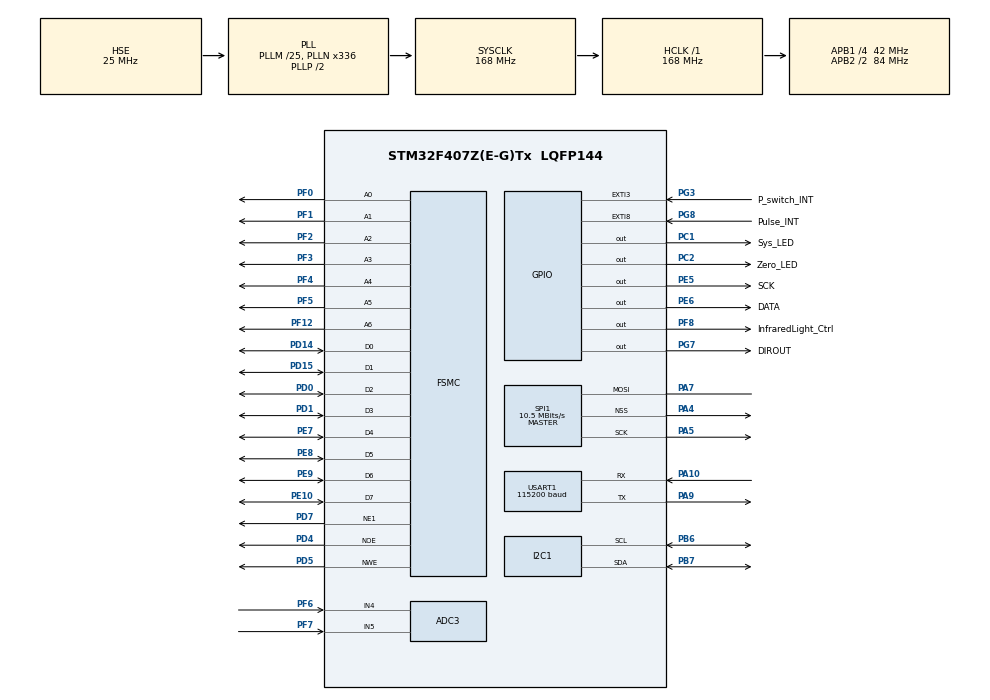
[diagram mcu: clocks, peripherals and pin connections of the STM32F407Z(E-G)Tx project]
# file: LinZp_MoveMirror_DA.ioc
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ADC3.Channel-0\#ChannelRegularConversion=ADC_CHANNEL_4
ADC3.NbrOfConversionFlag=1
ADC3.Rank-0\#ChannelRegularConversion=1
ADC3.SamplingTime-0\#ChannelRegularConversion=ADC_SAMPLETIME_3CYCLES
ADC3.ScanConvMode=ENABLE
Dma.I2C1_RX.0.Direction=DMA_PERIPH_TO_MEMORY
Dma.I2C1_RX.0.FIFOMode=DMA_FIFOMODE_DISABLE
Dma.I2C1_RX.0.Instance=DMA1_Stream0
Dma.I2C1_RX.0.MemDataAlignment=DMA_MDATAALIGN_BYTE
Dma.I2C1_RX.0.MemInc=DMA_MINC_ENABLE
Dma.I2C1_RX.0.Mode=DMA_NORMAL
Dma.I2C1_RX.0.PeriphDataAlignment=DMA_PDATAALIGN_BYTE
Dma.I2C1_RX.0.PeriphInc=DMA_PINC_DISABLE
Dma.I2C1_RX.0.Priority=DMA_PRIORITY_LOW
Dma.I2C1_TX.1.Direction=DMA_MEMORY_TO_PERIPH
Dma.I2C1_TX.1.FIFOMode=DMA_FIFOMODE_DISABLE
Dma.I2C1_TX.1.Instance=DMA1_Stream6
Dma.I2C1_TX.1.MemDataAlignment=DMA_MDATAALIGN_BYTE
Dma.I2C1_TX.1.MemInc=DMA_MINC_ENABLE
Dma.I2C1_TX.1.Mode=DMA_NORMAL
Dma.I2C1_TX.1.PeriphDataAlignment=DMA_PDATAALIGN_BYTE
Dma.I2C1_TX.1.PeriphInc=DMA_PINC_DISABLE
Dma.I2C1_TX.1.Priority=DMA_PRIORITY_LOW
Dma.Request0=I2C1_RX
Dma.Request1=I2C1_TX
Mcu.Family=STM32F4
Mcu.Name=STM32F407Z(E-G)Tx
Mcu.Package=LQFP144
NVIC.DMA1_Stream0_IRQn=true\:0\:0\:false\:false\:true\:false
NVIC.DMA1_Stream6_IRQn=true\:0\:0\:false\:false\:true\:false
NVIC.EXTI3_IRQn=true\:2\:0\:true\:false\:true\:true
NVIC.EXTI9_5_IRQn=true\:1\:0\:true\:false\:true\:true
NVIC.PriorityGroup=NVIC_PRIORITYGROUP_3
NVIC.TIM3_IRQn=true\:3\:0\:true\:false\:true\:true
NVIC.TIM4_IRQn=true\:4\:0\:true\:false\:true\:true
NVIC.USART1_IRQn=true\:0\:0\:true\:false\:true\:true
PA10.Mode=Asynchronous
PA10.Signal=USART1_RX
PA4.Mode=NSS_Signal_Hard_Output
PA4.Signal=SPI1_NSS
PA5.Mode=Simplex_Bidirectional_Master
PA5.Signal=SPI1_SCK
PA7.Mode=Simplex_Bidirectional_Master
PA7.Signal=SPI1_MOSI
PA9.Mode=Asynchronous
PA9.Signal=USART1_TX
PB6.Mode=I2C
PB6.Signal=I2C1_SCL
PB7.Mode=I2C
PB7.Signal=I2C1_SDA
PC1.GPIO_Label=Sys_LED
PC1.GPIO_PuPd=GPIO_PULLUP
PC1.GPIO_Speed=GPIO_SPEED_FREQ_HIGH
PC1.PinState=GPIO_PIN_SET
PC1.Signal=GPIO_Output
PC2.GPIO_Label=Zero_LED
PC2.GPIO_PuPd=GPIO_PULLUP
PC2.GPIO_Speed=GPIO_SPEED_FREQ_HIGH
PC2.PinState=GPIO_PIN_SET
PC2.Signal=GPIO_Output
PD0.Signal=FSMC_D2_DA2
PD1.Signal=FSMC_D3_DA3
PD14.Signal=FSMC_D0_DA0
PD15.Signal=FSMC_D1_DA1
PD4.Signal=FSMC_NOE
PD5.Signal=FSMC_NWE
PD7.Mode=NorPsramChipSelect1_1
PD7.Signal=FSMC_NE1
PE10.Signal=FSMC_D7_DA7
PE5.GPIO_Label=SCK
PE5.Signal=GPIO_Output
PE6.GPIO_Label=DATA
PE6.Signal=GPIO_Output
PE7.Signal=FSMC_D4_DA4
PE8.Signal=FSMC_D5_DA5
PE9.Signal=FSMC_D6_DA6
PF0.Signal=FSMC_A0
PF1.Signal=FSMC_A1
PF12.Signal=FSMC_A6
PF2.Signal=FSMC_A2
PF3.Signal=FSMC_A3
PF4.Signal=FSMC_A4
PF5.Signal=FSMC_A5
PF6.Mode=IN4
PF6.Signal=ADC3_IN4
PF7.Mode=IN5
PF7.Signal=ADC3_IN5
PF8.GPIO_Label=InfraredLight_Ctrl
PF8.GPIO_PuPd=GPIO_PULLDOWN
PF8.Signal=GPIO_Output
PG3.GPIO_Label=P_switch_INT
PG3.Signal=GPXTI3
PG7.GPIO_Label=DIROUT
PG7.GPIO_PuPd=GPIO_NOPULL
PG7.Signal=GPIO_Output
PG8.GPIO_Label=Pulse_INT
PG8.Signal=GPXTI8
PH0-OSC_IN.Mode=HSE-External-Oscillator
PH0-OSC_IN.Signal=RCC_OSC_IN
PH1-OSC_OUT.Mode=HSE-External-Oscillator
PH1-OSC_OUT.Signal=RCC_OSC_OUT
ProjectManager.HeapSize=0x200
ProjectManager.StackSize=0x400
ProjectManager.TargetToolchain=MDK-ARM V5
RCC.48MHZClocksFreq_Value=84000000
RCC.AHBFreq_Value=168000000
RCC.APB1CLKDivider=RCC_HCLK_DIV4
RCC.APB1Freq_Value=42000000
RCC.APB1TimFreq_Value=84000000
RCC.APB2CLKDivider=RCC_HCLK_DIV2
RCC.APB2Freq_Value=84000000
RCC.APB2TimFreq_Value=168000000
RCC.CortexFreq_Value=168000000
RCC.HCLKFreq_Value=168000000
RCC.HSE_VALUE=25000000
RCC.HSI_VALUE=16000000
RCC.LSE_VALUE=32768
RCC.PLLM=25
RCC.PLLN=336
RCC.PLLSourceVirtual=RCC_PLLSOURCE_HSE
RCC.SYSCLKFreq_VALUE=168000000
RCC.SYSCLKSource=RCC_SYSCLKSOURCE_PLLCLK
RCC.VCOOutputFreq_Value=336000000
SH.FSMC_A0.0=FSMC_A0,7b-a1
SH.FSMC_A1.0=FSMC_A1,7b-a1
SH.FSMC_A2.0=FSMC_A2,7b-a1
SH.FSMC_A3.0=FSMC_A3,7b-a1
SH.FSMC_A4.0=FSMC_A4,7b-a1
SH.FSMC_A5.0=FSMC_A5,7b-a1
SH.FSMC_A6.0=FSMC_A6,7b-a1
SH.FSMC_D0_DA0.0=FSMC_D0,8b-d1
SH.FSMC_D1_DA1.0=FSMC_D1,8b-d1
SH.FSMC_D2_DA2.0=FSMC_D2,8b-d1
SH.FSMC_D3_DA3.0=FSMC_D3,8b-d1
SH.FSMC_D4_DA4.0=FSMC_D4,8b-d1
SH.FSMC_D5_DA5.0=FSMC_D5,8b-d1
SH.FSMC_D6_DA6.0=FSMC_D6,8b-d1
SH.FSMC_D7_DA7.0=FSMC_D7,8b-d1
SH.FSMC_NOE.0=FSMC_NOE,Sram1
SH.FSMC_NWE.0=FSMC_NWE,Sram1
SPI1.BaudRatePrescaler=SPI_BAUDRATEPRESCALER_8
SPI1.CLKPhase=SPI_PHASE_2EDGE
SPI1.CalculateBaudRate=10.5 MBits/s
SPI1.Direction=SPI_DIRECTION_1LINE
SPI1.Mode=SPI_MODE_MASTER
SPI1.VirtualNSS=VM_NSSHARD
SPI1.VirtualType=VM_MASTER
TIM3.Period=1
TIM3.Prescaler=84
TIM4.Period=100
TIM4.Prescaler=84
USART1.BaudRate=115200
USART1.OverSampling=UART_OVERSAMPLING_8
USART1.VirtualMode=VM_ASYNC
VP_TIM3_VS_ClockSourceINT.Mode=Internal
VP_TIM4_VS_ClockSourceINT.Mode=Internal
board=MoveMirrorFinal_pwm

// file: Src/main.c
/**
  ******************************************************************************
  * @file           : main.c
  * @brief          : Main program body
  ******************************************************************************
  ** This notice applies to any and all portions of this file
  * that are not between comment pairs USER CODE BEGIN and
  * USER CODE END. Other portions of this file, whether
  * inserted by the user or by software development tools
  * are owned by their respective copyright owners.
  *
  * COPYRIGHT(c) 2018 STMicroelectronics
  *
  * Redistribution and use in source and binary forms, with or without modification,
  * are permitted provided that the following conditions are met:
  *   1. Redistributions of source code must retain the above copyright notice,
  *      this list of conditions and the following disclaimer.
  *   2. Redistributions in binary form must reproduce the above copyright notice,
  *      this list of conditions and the following disclaimer in the documentation
  *      and/or other materials provided with the distribution.
  *   3. Neither the name of STMicroelectronics nor the names of its contributors
  *      may be used to endorse or promote products derived from this software
  *      without specific prior written permission.
  *
  * THIS SOFTWARE IS PROVIDED BY THE COPYRIGHT HOLDERS AND CONTRIBUTORS "AS IS"
  * AND ANY EXPRESS OR IMPLIED WARRANTIES, INCLUDING, BUT NOT LIMITED TO, THE
  * IMPLIED WARRANTIES OF MERCHANTABILITY AND FITNESS FOR A PARTICULAR PURPOSE ARE
  * DISCLAIMED. IN NO EVENT SHALL THE COPYRIGHT HOLDER OR CONTRIBUTORS BE LIABLE
  * FOR ANY DIRECT, INDIRECT, INCIDENTAL, SPECIAL, EXEMPLARY, OR CONSEQUENTIAL
  * DAMAGES (INCLUDING, BUT NOT LIMITED TO, PROCUREMENT OF SUBSTITUTE GOODS OR
  * SERVICES; LOSS OF USE, DATA, OR PROFITS; OR BUSINESS INTERRUPTION) HOWEVER
  * CAUSED AND ON ANY THEORY OF LIABILITY, WHETHER IN CONTRACT, STRICT LIABILITY,
  * OR TORT (INCLUDING NEGLIGENCE OR OTHERWISE) ARISING IN ANY WAY OUT OF THE USE
  * OF THIS SOFTWARE, EVEN IF ADVISED OF THE POSSIBILITY OF SUCH DAMAGE.
  *
  ******************************************************************************
  */
#include "main.h"
#include "stm32f4xx_hal.h"

/* USER CODE BEGIN Includes */
#include "sys.h"
/* USER CODE END Includes */

ADC_HandleTypeDef hadc3;

I2C_HandleTypeDef hi2c1;
DMA_HandleTypeDef hdma_i2c1_rx;
DMA_HandleTypeDef hdma_i2c1_tx;

SPI_HandleTypeDef hspi1;

TIM_HandleTypeDef htim3;
TIM_HandleTypeDef htim4;

UART_HandleTypeDef huart1;

SRAM_HandleTypeDef hsram1;

/* USER CODE BEGIN PV */
/* Private variables ---------------------------------------------------------*/

/* USER CODE END PV */

void SystemClock_Config(void);
static void MX_GPIO_Init(void);
static void MX_DMA_Init(void);
static void MX_FSMC_Init(void);
static void MX_USART1_UART_Init(void);
static void MX_TIM3_Init(void);
static void MX_TIM4_Init(void);
static void MX_SPI1_Init(void);
static void MX_I2C1_Init(void);
static void MX_ADC3_Init(void);

/* USER CODE BEGIN PFP */
/* Private function prototypes -----------------------------------------------*/

/* USER CODE END PFP */

int main(void)
{

  /* MCU Configuration----------------------------------------------------------*/

  /* Reset of all peripherals, Initializes the Flash interface and the Systick. */
  HAL_Init();

  /* Configure the system clock */
  SystemClock_Config();

  /* Initialize all configured peripherals */
  MX_GPIO_Init();
  MX_DMA_Init();
  MX_FSMC_Init();
  MX_USART1_UART_Init();
  MX_TIM3_Init();
  MX_TIM4_Init();
  MX_SPI1_Init();
  MX_I2C1_Init();
  MX_ADC3_Init();
  /* USER CODE BEGIN 2 */
	DAC_init();
	HAL_UART_Receive_IT(&huart1,&Uart1_Data,1);//给接收到的数据定向，存在Uart1_Data_buffer[10]//__HAL_UART_ENABLE_IT(&huart1,UART_IT_RXNE); //开启接收完成中断
	//HAL_UART_Receive_IT(&huart3,&Uart3_Data,1);//给接收到的数据定向，存在Uart1_Data_buffer[10]//__HAL_UART_ENABLE_IT(&huart1,UART_IT_RXNE); //开启接收完成中断

	//HAL_Delay_ms(15000);
	////////////////////////////////////////////////////////////////////////////
	AD5245_Write(LightIntensity);//给AD5245写入初始值0x35=53，6.4v//8是10.6V

	//HAL_TIM_PWM_Start(&htim8,TIM_CHANNEL_1);//tim8开启 PWM 通道 1
	ResetCount = 0;       //复位计数
	ProcessFlag=ResetFlag;//开机复位
	//ProcessFlag=DebugFlag;//开机复位
	SystemReset();
	HAL_TIM_Base_Start_IT(&htim3);   //tim3中断开启,用于动镜的加速和减速
	HAL_TIM_Base_Start_IT(&htim4);   //tim4中断开启，用于调试信息输出，以及运动失调的复位
  /* USER CODE END 2 */

  /* Infinite loop */
  while (1)
  {

  /* USER CODE BEGIN 3 */
	//	SetOutput(-584287);

	//uint8_t ADDR_AD5245_Write = 0x58;//01011000
	//uint8_t data = 0x35;//53
	//HAL_I2C_Mem_Write(&hi2c1, ADDR_AD5245_Write, 0, I2C_MEMADD_SIZE_8BIT,&data,1,0xff);
//	HAL_I2C_Master_Transmit_DMA(&hi2c1,ADDR_AD5245_Write,&data,1);

//	ADC_Value4 = Get_Adc(4);
//	ADC_Value5 = Get_Adc(5);

//	HAL_Delay(5);
//	HAL_I2C_Mem_Write(&hi2c1, ADDR_24LCxx_Read, 0, I2C_MEMADD_SIZE_8BIT,&val,1,0xff);

		//SetOutput(300000);
	//	Write_AD_5791(320000);
//		HAL_Delay_ms(1000);
//		HAL_GPIO_WritePin(GPIOC, GPIO_PIN_1, GPIO_PIN_RESET);
//		HAL_Delay_ms(1000);
//		HAL_GPIO_WritePin(GPIOC, GPIO_PIN_1, GPIO_PIN_SET);
  }
  /* USER CODE END 3 */

}

void SystemClock_Config(void)
{

  RCC_OscInitTypeDef RCC_OscInitStruct;
  RCC_ClkInitTypeDef RCC_ClkInitStruct;

    /**Configure the main internal regulator output voltage
    */
  __HAL_RCC_PWR_CLK_ENABLE();

  __HAL_PWR_VOLTAGESCALING_CONFIG(PWR_REGULATOR_VOLTAGE_SCALE1);

    /**Initializes the CPU, AHB and APB busses clocks
    */
  RCC_OscInitStruct.OscillatorType = RCC_OSCILLATORTYPE_HSE;
  RCC_OscInitStruct.HSEState = RCC_HSE_ON;
  RCC_OscInitStruct.PLL.PLLState = RCC_PLL_ON;
  RCC_OscInitStruct.PLL.PLLSource = RCC_PLLSOURCE_HSE;
  RCC_OscInitStruct.PLL.PLLM = 25;
  RCC_OscInitStruct.PLL.PLLN = 336;
  RCC_OscInitStruct.PLL.PLLP = RCC_PLLP_DIV2;
  RCC_OscInitStruct.PLL.PLLQ = 4;
  if (HAL_RCC_OscConfig(&RCC_OscInitStruct) != HAL_OK)
  {
    _Error_Handler(__FILE__, __LINE__);
  }

    /**Initializes the CPU, AHB and APB busses clocks
    */
  RCC_ClkInitStruct.ClockType = RCC_CLOCKTYPE_HCLK|RCC_CLOCKTYPE_SYSCLK
                              |RCC_CLOCKTYPE_PCLK1|RCC_CLOCKTYPE_PCLK2;
  RCC_ClkInitStruct.SYSCLKSource = RCC_SYSCLKSOURCE_PLLCLK;
  RCC_ClkInitStruct.AHBCLKDivider = RCC_SYSCLK_DIV1;
  RCC_ClkInitStruct.APB1CLKDivider = RCC_HCLK_DIV4;
  RCC_ClkInitStruct.APB2CLKDivider = RCC_HCLK_DIV2;

  if (HAL_RCC_ClockConfig(&RCC_ClkInitStruct, FLASH_LATENCY_5) != HAL_OK)
  {
    _Error_Handler(__FILE__, __LINE__);
  }

    /**Configure the Systick interrupt time
    */
  HAL_SYSTICK_Config(HAL_RCC_GetHCLKFreq()/1000);

    /**Configure the Systick
    */
  HAL_SYSTICK_CLKSourceConfig(SYSTICK_CLKSOURCE_HCLK);

  /* SysTick_IRQn interrupt configuration */
  HAL_NVIC_SetPriority(SysTick_IRQn, 0, 0);
}

/* ADC3 init function */
static void MX_ADC3_Init(void)
{

  ADC_ChannelConfTypeDef sConfig;

    /**Configure the global features of the ADC (Clock, Resolution, Data Alignment and number of conversion)
    */
  hadc3.Instance = ADC3;
  hadc3.Init.ClockPrescaler = ADC_CLOCK_SYNC_PCLK_DIV4;
  hadc3.Init.Resolution = ADC_RESOLUTION_12B;
  hadc3.Init.ScanConvMode = ENABLE;
  hadc3.Init.ContinuousConvMode = DISABLE;
  hadc3.Init.DiscontinuousConvMode = DISABLE;
  hadc3.Init.ExternalTrigConvEdge = ADC_EXTERNALTRIGCONVEDGE_NONE;
  hadc3.Init.ExternalTrigConv = ADC_SOFTWARE_START;
  hadc3.Init.DataAlign = ADC_DATAALIGN_RIGHT;
  hadc3.Init.NbrOfConversion = 1;
  hadc3.Init.DMAContinuousRequests = DISABLE;
  hadc3.Init.EOCSelection = ADC_EOC_SINGLE_CONV;
  if (HAL_ADC_Init(&hadc3) != HAL_OK)
  {
    _Error_Handler(__FILE__, __LINE__);
  }

    /**Configure for the selected ADC regular channel its corresponding rank in the sequencer and its sample time.
    */
  sConfig.Channel = ADC_CHANNEL_4;
  sConfig.Rank = 1;
  sConfig.SamplingTime = ADC_SAMPLETIME_3CYCLES;
  if (HAL_ADC_ConfigChannel(&hadc3, &sConfig) != HAL_OK)
  {
    _Error_Handler(__FILE__, __LINE__);
  }

}

/* I2C1 init function */
static void MX_I2C1_Init(void)
{

  hi2c1.Instance = I2C1;
  hi2c1.Init.ClockSpeed = 100000;
  hi2c1.Init.DutyCycle = I2C_DUTYCYCLE_2;
  hi2c1.Init.OwnAddress1 = 0;
  hi2c1.Init.AddressingMode = I2C_ADDRESSINGMODE_7BIT;
  hi2c1.Init.DualAddressMode = I2C_DUALADDRESS_DISABLE;
  hi2c1.Init.OwnAddress2 = 0;
  hi2c1.Init.GeneralCallMode = I2C_GENERALCALL_DISABLE;
  hi2c1.Init.NoStretchMode = I2C_NOSTRETCH_DISABLE;
  if (HAL_I2C_Init(&hi2c1) != HAL_OK)
  {
    _Error_Handler(__FILE__, __LINE__);
  }

}

/* SPI1 init function */
static void MX_SPI1_Init(void)
{

  /* SPI1 parameter configuration*/
  hspi1.Instance = SPI1;
  hspi1.Init.Mode = SPI_MODE_MASTER;
  hspi1.Init.Direction = SPI_DIRECTION_1LINE;
  hspi1.Init.DataSize = SPI_DATASIZE_8BIT;
  hspi1.Init.CLKPolarity = SPI_POLARITY_LOW;
  hspi1.Init.CLKPhase = SPI_PHASE_2EDGE;
  hspi1.Init.NSS = SPI_NSS_HARD_OUTPUT;
  hspi1.Init.BaudRatePrescaler = SPI_BAUDRATEPRESCALER_8;
  hspi1.Init.FirstBit = SPI_FIRSTBIT_MSB;
  hspi1.Init.TIMode = SPI_TIMODE_DISABLE;
  hspi1.Init.CRCCalculation = SPI_CRCCALCULATION_DISABLE;
  hspi1.Init.CRCPolynomial = 10;
  if (HAL_SPI_Init(&hspi1) != HAL_OK)
  {
    _Error_Handler(__FILE__, __LINE__);
  }

}

/* TIM3 init function */
static void MX_TIM3_Init(void)
{

  TIM_ClockConfigTypeDef sClockSourceConfig;
  TIM_MasterConfigTypeDef sMasterConfig;

  htim3.Instance = TIM3;
  htim3.Init.Prescaler = 84;
  htim3.Init.CounterMode = TIM_COUNTERMODE_UP;
  htim3.Init.Period = 1;
  htim3.Init.ClockDivision = TIM_CLOCKDIVISION_DIV1;
  if (HAL_TIM_Base_Init(&htim3) != HAL_OK)
  {
    _Error_Handler(__FILE__, __LINE__);
  }

  sClockSourceConfig.ClockSource = TIM_CLOCKSOURCE_INTERNAL;
  if (HAL_TIM_ConfigClockSource(&htim3, &sClockSourceConfig) != HAL_OK)
  {
    _Error_Handler(__FILE__, __LINE__);
  }

  sMasterConfig.MasterOutputTrigger = TIM_TRGO_RESET;
  sMasterConfig.MasterSlaveMode = TIM_MASTERSLAVEMODE_DISABLE;
  if (HAL_TIMEx_MasterConfigSynchronization(&htim3, &sMasterConfig) != HAL_OK)
  {
    _Error_Handler(__FILE__, __LINE__);
  }

}

/* TIM4 init function */
static void MX_TIM4_Init(void)
{

  TIM_ClockConfigTypeDef sClockSourceConfig;
  TIM_MasterConfigTypeDef sMasterConfig;

  htim4.Instance = TIM4;
  htim4.Init.Prescaler = 84;
  htim4.Init.CounterMode = TIM_COUNTERMODE_UP;
  htim4.Init.Period = 100;
  htim4.Init.ClockDivision = TIM_CLOCKDIVISION_DIV1;
  if (HAL_TIM_Base_Init(&htim4) != HAL_OK)
  {
    _Error_Handler(__FILE__, __LINE__);
  }

  sClockSourceConfig.ClockSource = TIM_CLOCKSOURCE_INTERNAL;
  if (HAL_TIM_ConfigClockSource(&htim4, &sClockSourceConfig) != HAL_OK)
  {
    _Error_Handler(__FILE__, __LINE__);
  }

  sMasterConfig.MasterOutputTrigger = TIM_TRGO_RESET;
  sMasterConfig.MasterSlaveMode = TIM_MASTERSLAVEMODE_DISABLE;
  if (HAL_TIMEx_MasterConfigSynchronization(&htim4, &sMasterConfig) != HAL_OK)
  {
    _Error_Handler(__FILE__, __LINE__);
  }

}

/* USART1 init function */
static void MX_USART1_UART_Init(void)
{

  huart1.Instance = USART1;
  huart1.Init.BaudRate = 115200;
  huart1.Init.WordLength = UART_WORDLENGTH_8B;
  huart1.Init.StopBits = UART_STOPBITS_1;
  huart1.Init.Parity = UART_PARITY_NONE;
  huart1.Init.Mode = UART_MODE_TX_RX;
  huart1.Init.HwFlowCtl = UART_HWCONTROL_NONE;
  huart1.Init.OverSampling = UART_OVERSAMPLING_8;
  if (HAL_UART_Init(&huart1) != HAL_OK)
  {
    _Error_Handler(__FILE__, __LINE__);
  }

}

static void MX_DMA_Init(void)
{
  /* DMA controller clock enable */
  __HAL_RCC_DMA1_CLK_ENABLE();

  /* DMA interrupt init */
  /* DMA1_Stream0_IRQn interrupt configuration */
  HAL_NVIC_SetPriority(DMA1_Stream0_IRQn, 0, 0);
  HAL_NVIC_EnableIRQ(DMA1_Stream0_IRQn);
  /* DMA1_Stream6_IRQn interrupt configuration */
  HAL_NVIC_SetPriority(DMA1_Stream6_IRQn, 0, 0);
  HAL_NVIC_EnableIRQ(DMA1_Stream6_IRQn);

}

/** Configure pins as
        * Analog
        * Input
        * Output
        * EVENT_OUT
        * EXTI
*/
static void MX_GPIO_Init(void)
{

  GPIO_InitTypeDef GPIO_InitStruct;

  /* GPIO Ports Clock Enable */
  __HAL_RCC_GPIOE_CLK_ENABLE();
  __HAL_RCC_GPIOF_CLK_ENABLE();
  __HAL_RCC_GPIOH_CLK_ENABLE();
  __HAL_RCC_GPIOC_CLK_ENABLE();
  __HAL_RCC_GPIOA_CLK_ENABLE();
  __HAL_RCC_GPIOD_CLK_ENABLE();
  __HAL_RCC_GPIOG_CLK_ENABLE();
  __HAL_RCC_GPIOB_CLK_ENABLE();

  /*Configure GPIO pin Output Level */
  HAL_GPIO_WritePin(GPIOE, SCK_Pin|DATA_Pin, GPIO_PIN_RESET);

  /*Configure GPIO pin Output Level */
  HAL_GPIO_WritePin(InfraredLight_Ctrl_GPIO_Port, InfraredLight_Ctrl_Pin, GPIO_PIN_RESET);

  /*Configure GPIO pin Output Level */
  HAL_GPIO_WritePin(GPIOC, GPIO_PIN_1|GPIO_PIN_2, GPIO_PIN_SET);

  /*Configure GPIO pin Output Level */
  HAL_GPIO_WritePin(GPIOG, GPIO_PIN_2|GPIO_PIN_7, GPIO_PIN_RESET);

  /*Configure GPIO pin Output Level */
  HAL_GPIO_WritePin(GPIOC, GPIO_PIN_7|GPIO_PIN_8|GPIO_PIN_9, GPIO_PIN_RESET);

  /*Configure GPIO pins : SCK_Pin DATA_Pin */
  GPIO_InitStruct.Pin = SCK_Pin|DATA_Pin;
  GPIO_InitStruct.Mode = GPIO_MODE_OUTPUT_PP;
  GPIO_InitStruct.Pull = GPIO_NOPULL;
  GPIO_InitStruct.Speed = GPIO_SPEED_FREQ_LOW;
  HAL_GPIO_Init(GPIOE, &GPIO_InitStruct);

  /*Configure GPIO pin : InfraredLight_Ctrl_Pin */
  GPIO_InitStruct.Pin = InfraredLight_Ctrl_Pin;
  GPIO_InitStruct.Mode = GPIO_MODE_OUTPUT_PP;
  GPIO_InitStruct.Pull = GPIO_PULLDOWN;
  GPIO_InitStruct.Speed = GPIO_SPEED_FREQ_LOW;
  HAL_GPIO_Init(InfraredLight_Ctrl_GPIO_Port, &GPIO_InitStruct);

  /*Configure GPIO pins : PC1 PC2 */
  GPIO_InitStruct.Pin = GPIO_PIN_1|GPIO_PIN_2;
  GPIO_InitStruct.Mode = GPIO_MODE_OUTPUT_PP;
  GPIO_InitStruct.Pull = GPIO_PULLUP;
  GPIO_InitStruct.Speed = GPIO_SPEED_FREQ_HIGH;
  HAL_GPIO_Init(GPIOC, &GPIO_InitStruct);

  /*Configure GPIO pins : PG2 PG7 */
  GPIO_InitStruct.Pin = GPIO_PIN_2|GPIO_PIN_7;
  GPIO_InitStruct.Mode = GPIO_MODE_OUTPUT_PP;
  GPIO_InitStruct.Pull = GPIO_NOPULL;
  GPIO_InitStruct.Speed = GPIO_SPEED_FREQ_LOW;
  HAL_GPIO_Init(GPIOG, &GPIO_InitStruct);

  /*Configure GPIO pins : PG3 PG8 */
  GPIO_InitStruct.Pin = GPIO_PIN_3|GPIO_PIN_8;
  GPIO_InitStruct.Mode = GPIO_MODE_IT_RISING;
  GPIO_InitStruct.Pull = GPIO_NOPULL;
  HAL_GPIO_Init(GPIOG, &GPIO_InitStruct);

  /*Configure GPIO pins : PC7 PC8 PC9 */
  GPIO_InitStruct.Pin = GPIO_PIN_7|GPIO_PIN_8|GPIO_PIN_9;
  GPIO_InitStruct.Mode = GPIO_MODE_OUTPUT_PP;
  GPIO_InitStruct.Pull = GPIO_NOPULL;
  GPIO_InitStruct.Speed = GPIO_SPEED_FREQ_LOW;
  HAL_GPIO_Init(GPIOC, &GPIO_InitStruct);

  /* EXTI interrupt init*/
  HAL_NVIC_SetPriority(EXTI3_IRQn, 2, 0);
  HAL_NVIC_EnableIRQ(EXTI3_IRQn);

  HAL_NVIC_SetPriority(EXTI9_5_IRQn, 1, 0);
  HAL_NVIC_EnableIRQ(EXTI9_5_IRQn);

}

/* FSMC initialization function */
static void MX_FSMC_Init(void)
{
  FSMC_NORSRAM_TimingTypeDef Timing;

  /** Perform the SRAM1 memory initialization sequence
  */
  hsram1.Instance = FSMC_NORSRAM_DEVICE;
  hsram1.Extended = FSMC_NORSRAM_EXTENDED_DEVICE;
  /* hsram1.Init */
  hsram1.Init.NSBank = FSMC_NORSRAM_BANK1;
  hsram1.Init.DataAddressMux = FSMC_DATA_ADDRESS_MUX_DISABLE;
  hsram1.Init.MemoryType = FSMC_MEMORY_TYPE_SRAM;
  hsram1.Init.MemoryDataWidth = FSMC_NORSRAM_MEM_BUS_WIDTH_8;
  hsram1.Init.BurstAccessMode = FSMC_BURST_ACCESS_MODE_DISABLE;
  hsram1.Init.WaitSignalPolarity = FSMC_WAIT_SIGNAL_POLARITY_LOW;
  hsram1.Init.WrapMode = FSMC_WRAP_MODE_DISABLE;
  hsram1.Init.WaitSignalActive = FSMC_WAIT_TIMING_BEFORE_WS;
  hsram1.Init.WriteOperation = FSMC_WRITE_OPERATION_DISABLE;
  hsram1.Init.WaitSignal = FSMC_WAIT_SIGNAL_DISABLE;
  hsram1.Init.ExtendedMode = FSMC_EXTENDED_MODE_DISABLE;
  hsram1.Init.AsynchronousWait = FSMC_ASYNCHRONOUS_WAIT_DISABLE;
  hsram1.Init.WriteBurst = FSMC_WRITE_BURST_DISABLE;
  hsram1.Init.PageSize = FSMC_PAGE_SIZE_NONE;
  /* Timing */
  Timing.AddressSetupTime = 15;
  Timing.AddressHoldTime = 15;
  Timing.DataSetupTime = 255;
  Timing.BusTurnAroundDuration = 15;
  Timing.CLKDivision = 16;
  Timing.DataLatency = 17;
  Timing.AccessMode = FSMC_ACCESS_MODE_A;
  /* ExtTiming */

  if (HAL_SRAM_Init(&hsram1, &Timing, NULL) != HAL_OK)
  {
    _Error_Handler(__FILE__, __LINE__);
  }

}

void _Error_Handler(char *file, int line)
{
  while(1)
  {
  }
}

/************************ (C) COPYRIGHT STMicroelectronics *****END OF FILE****/
